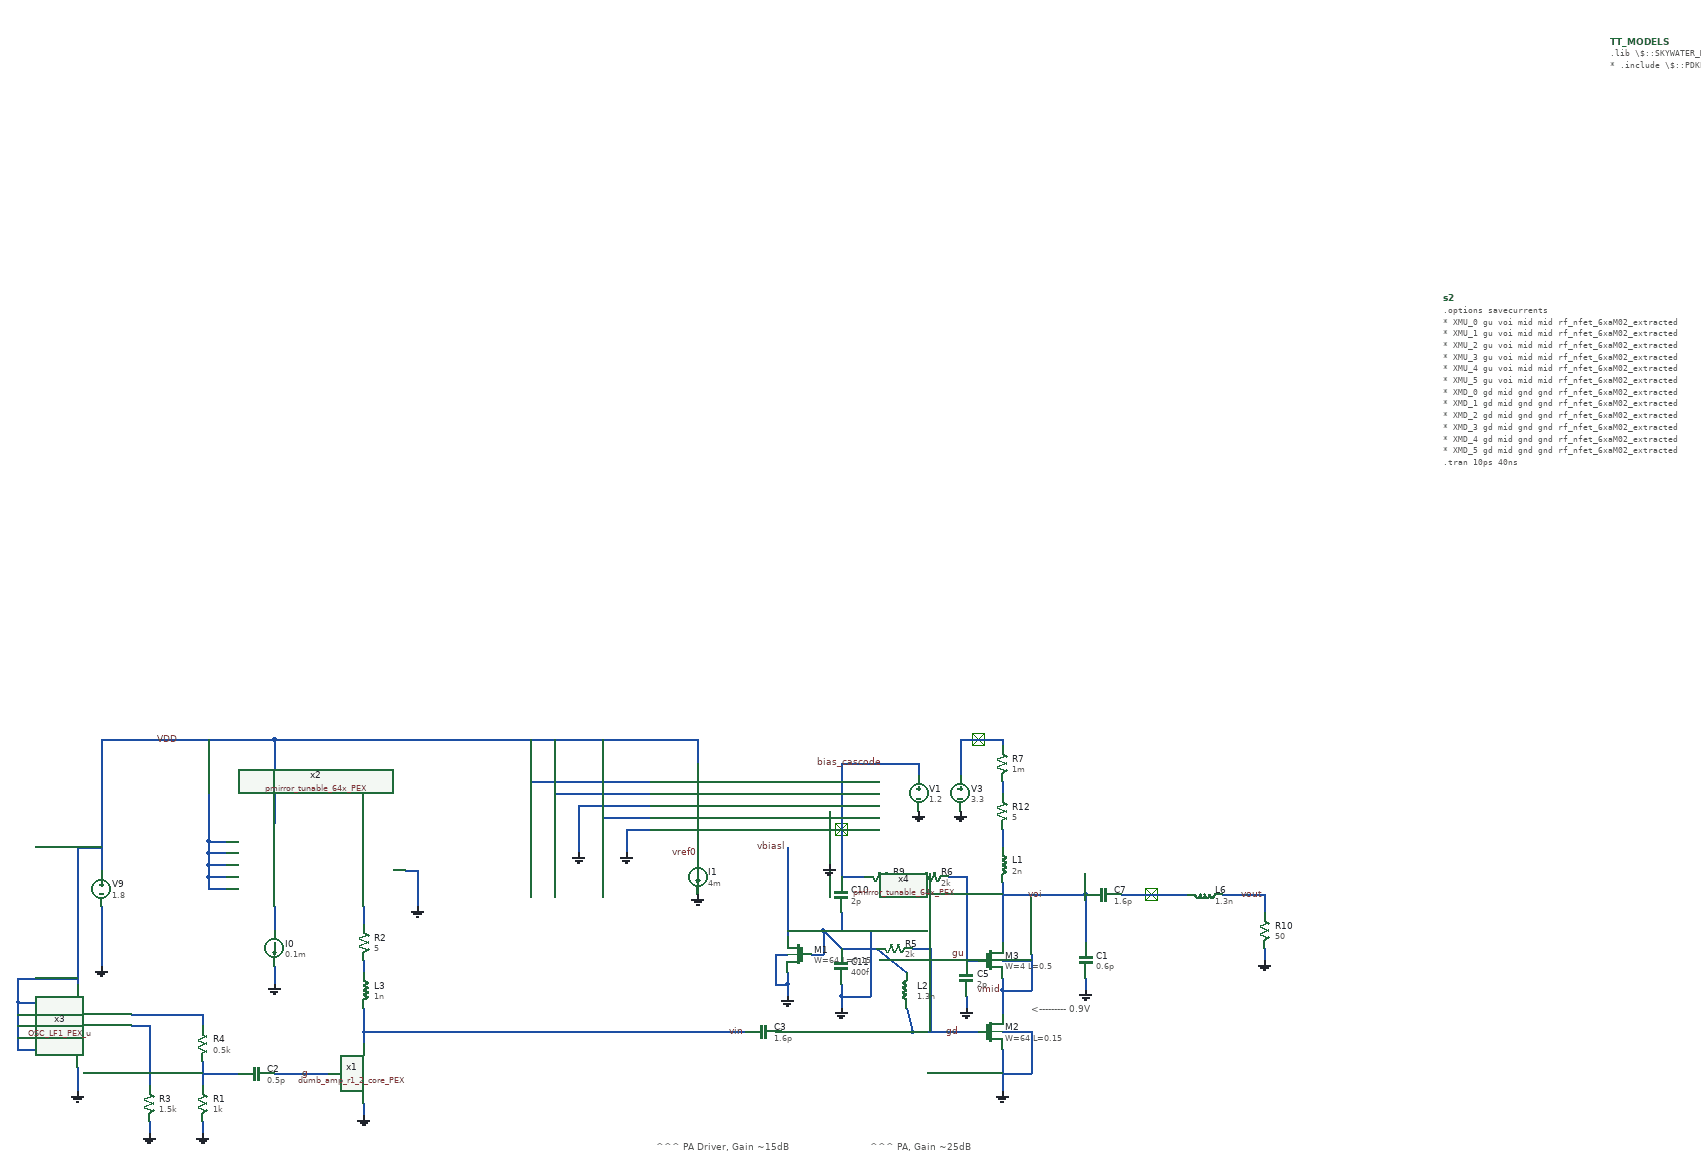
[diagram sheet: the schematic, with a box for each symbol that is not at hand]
v {xschem version=3.0.0 file_version=1.2 }
G {}
K {}
V {}
S {}
E {}
L 4 730 -310 730 -290 {}
L 4 730 -290 750 -290 {}
L 4 750 -310 750 -290 {}
L 4 730 -310 750 -310 {}
L 4 730 -310 750 -290 {}
L 4 750 -310 750 -290 {}
L 4 730 -290 750 -310 {}
L 4 1020 -50 1020 -30 {}
L 4 1020 -30 1040 -30 {}
L 4 1040 -50 1040 -30 {}
L 4 1020 -50 1040 -50 {}
L 4 1020 -50 1040 -30 {}
L 4 1020 -30 1040 -50 {}
L 4 500 -160 500 -140 {}
L 4 500 -140 520 -140 {}
L 4 520 -160 520 -140 {}
L 4 500 -160 520 -160 {}
L 4 500 -160 520 -140 {}
L 4 520 -160 520 -140 {}
L 4 500 -140 520 -160 {}
T {<--------- 0.9V} 830 140 0 0 0.4 0.4 {}
T {^^^ PA Driver, Gain ~15dB} 200 370 0 0 0.4 0.4 {}
T {^^^ PA, Gain ~25dB} 560 370 0 0 0.4 0.4 {}
N 780 -60 780 -10 {
lab=voi}
N 630 190 720 190 {
lab=gd}
N 710 -300 710 -240 {
lab=#net1}
N 710 -300 780 -300 {
lab=#net1}
N 1220 50 1220 70 {
lab=GND}
N 1150 -40 1220 -40 {
lab=vout}
N 1220 -40 1220 -10 {
lab=vout}
N 920 -40 920 -30 {
lab=voi}
N 830 60 830 120 {
lab=vmid}
N 780 120 830 120 {
lab=vmid}
N 920 100 920 120 {
lab=GND}
N 920 -40 920 40 {
lab=voi}
N 780 100 780 120 {
lab=vmid}
N 720 70 740 70 {
lab=gu}
N 720 60 720 70 {
lab=gu}
N 780 -10 780 40 {
lab=voi}
N 780 70 830 70 {
lab=vmid}
N 780 120 780 160 {
lab=vmid}
N 720 190 740 190 {
lab=gd}
N 780 220 780 250 {
lab=GND}
N 780 190 830 190 {
lab=GND}
N 720 130 720 150 {
lab=GND}
N 780 -300 780 -290 {
lab=#net1}
N 780 -230 780 -210 {
lab=#net2}
N 780 250 780 290 {
lab=GND}
N 780 -150 780 -120 {
lab=#net3}
N 420 -0 420 30 {
lab=vbiasl}
N 400 60 420 60 {
lab=GND}
N 400 60 400 110 {
lab=GND}
N 400 110 420 110 {
lab=GND}
N 420 90 420 110 {
lab=GND}
N 420 110 420 130 {
lab=GND}
N 460 60 480 60 {
lab=vbiasl}
N 480 20 480 60 {
lab=vbiasl}
N 420 20 480 20 {
lab=vbiasl}
N 510 -10 510 20 {
lab=GND}
N 510 20 560 20 {
lab=GND}
N 560 20 560 130 {
lab=GND}
N 510 130 560 130 {
lab=GND}
N 510 110 510 130 {
lab=GND}
N 510 130 510 150 {
lab=GND}
N 510 50 570 50 {
lab=vbiasl}
N 720 -70 720 60 {
lab=gu}
N 630 50 660 50 {
lab=gd}
N 660 50 660 190 {
lab=gd}
N 510 -70 550 -70 {
lab=bias_cascode}
N 830 190 830 260 {
lab=GND}
N 780 260 830 260 {
lab=GND}
N 400 190 480 190 {
lab=gd}
N 540 190 570 190 {
lab=gd}
N 480 190 510 190 {
lab=gd}
N 510 190 540 190 {
lab=gd}
N 480 20 510 50 {
lab=vbiasl}
N 270 190 280 190 {
lab=vin}
N 230 190 270 190 {
lab=vin}
N -440 -260 -440 -160 {
lab=VDD}
N 40 190 170 190 {
lab=vin}
N 280 190 350 190 {
lab=vin}
N 780 -40 920 -40 {
lab=voi}
N 620 150 630 190 {
lab=gd}
N 570 50 620 90 {
lab=vbiasl}
N 170 190 230 190 {
lab=vin}
N 980 -40 1090 -40 {
lab=#net4}
N -550 -260 -550 -130 {
lab=VDD}
N 690 -70 720 -70 {
lab=gu}
N 610 -70 630 -70 {
lab=#net5}
N 640 -260 640 -240 {
lab=bias_cascode}
N 590 -260 640 -260 {
lab=bias_cascode}
N 580 -260 590 -260 {
lab=bias_cascode}
N 510 -260 580 -260 {
lab=bias_cascode}
N 510 -260 510 -70 {
lab=bias_cascode}
N 490 -180 490 -90 {
lab=GND}
N 270 -300 270 -260 {
lab=VDD}
N -440 -300 270 -300 {
lab=VDD}
N -550 -300 -550 -260 {
lab=VDD}
N -440 -300 -440 -260 {
lab=VDD}
N 270 -120 270 -100 {
lab=vref0}
N -10 -230 190 -230 {
lab=G2}
N 30 -210 190 -210 {
lab=VDD}
N 70 -190 190 -190 {
lab=GND}
N 110 -170 190 -170 {
lab=VDD}
N 150 -150 190 -150 {
lab=GND}
N 420 -120 420 -0 {
lab=vbiasl}
N 150 -150 150 -110 {
lab=GND}
N 110 -300 110 -170 {
lab=VDD}
N 30 -300 30 -210 {
lab=VDD}
N -10 -300 -10 -230 {
lab=VDD}
N 70 -190 70 -110 {
lab=GND}
N -290 310 -290 330 {
lab=GND}
N -290 190 -250 190 {
lab=vin}
N -290 70 -290 90 {
lab=#net6}
N -440 80 -440 110 {
lab=GND}
N -440 -20 -440 20 {
lab=#net7}
N -730 -20 -730 80 {
lab=GND}
N -290 150 -290 190 {
lab=vin}
N -290 70 -290 90 {
lab=#net6}
N -440 80 -440 110 {
lab=GND}
N -290 150 -290 190 {
lab=vin}
N -560 240 -560 280 {
lab=#net8}
N -560 260 -500 260 {
lab=#net8}
N -560 340 -560 360 {
lab=GND}
N -680 160 -560 160 {
lab=#net9}
N -290 190 -290 210 {
lab=vin}
N -440 260 -350 260 {
lab=g}
N -290 -20 -290 10 {
lab=#net10}
N -220 -80 -200 -80 {
lab=GND}
N -200 -80 -200 -20 {
lab=GND}
N -550 -130 -520 -130 {
lab=VDD}
N -550 -130 -550 -110 {
lab=VDD}
N -550 -110 -520 -110 {
lab=VDD}
N -550 -110 -550 -90 {
lab=VDD}
N -550 -90 -520 -90 {
lab=VDD}
N -550 -90 -550 -70 {
lab=VDD}
N -550 -70 -520 -70 {
lab=VDD}
N -550 -70 -550 -50 {
lab=VDD}
N -550 -50 -520 -50 {
lab=VDD}
N -560 160 -560 180 {
lab=#net9}
N -650 340 -650 360 {
lab=GND}
N -650 180 -650 280 {
lab=#net11}
N -680 180 -650 180 {
lab=#net11}
N -770 -120 -770 110 {
lab=VDD}
N -770 -120 -730 -120 {
lab=VDD}
N -770 250 -770 290 {
lab=GND}
N -870 220 -840 220 {
lab=VDD}
N -870 140 -870 220 {
lab=VDD}
N -870 140 -840 140 {
lab=VDD}
N -870 160 -840 160 {
lab=VDD}
N -870 180 -840 180 {
lab=VDD}
N -870 200 -840 200 {
lab=VDD}
N -870 100 -870 140 {
lab=VDD}
N -870 100 -770 100 {
lab=VDD}
N -730 -300 -730 -80 {
lab=VDD}
N -730 -300 -440 -300 {
lab=VDD}
N -250 190 40 190 {
lab=vin}
N 570 190 630 190 {
lab=gd}
C {devices/code.sym} 1800 -1470 0 0 {name=TT_MODELS only_toplevel=false
format="tcleval(@value )" value=".lib \\\\$::SKYWATER_MODELS\\\\/sky130.lib.spice tt
* .include \\\\$::PDKPATH\\\\/libs.ref/sky130_fd_sc_hvl/spice/sky130_fd_sc_hvl.spice
"}
C {devices/code_shown.sym} 1520 -1040 0 0 {name=s2 only_toplevel=false value="
.options savecurrents
* XMU_0 gu voi mid mid rf_nfet_6xaM02_extracted
* XMU_1 gu voi mid mid rf_nfet_6xaM02_extracted
* XMU_2 gu voi mid mid rf_nfet_6xaM02_extracted
* XMU_3 gu voi mid mid rf_nfet_6xaM02_extracted
* XMU_4 gu voi mid mid rf_nfet_6xaM02_extracted
* XMU_5 gu voi mid mid rf_nfet_6xaM02_extracted
* XMD_0 gd mid gnd gnd rf_nfet_6xaM02_extracted
* XMD_1 gd mid gnd gnd rf_nfet_6xaM02_extracted
* XMD_2 gd mid gnd gnd rf_nfet_6xaM02_extracted
* XMD_3 gd mid gnd gnd rf_nfet_6xaM02_extracted
* XMD_4 gd mid gnd gnd rf_nfet_6xaM02_extracted
* XMD_5 gd mid gnd gnd rf_nfet_6xaM02_extracted
.tran 10ps 40ns
* .sp dec 1000 1e9 10e9 1
* .dc I1 0 10m 0.1m
.control
run
display
* plot @r5[i]
* let zout=@rload[r]
* let zin=50
* plot voi
* plot vout
* plot @c1[i]

plot vbiasl
plot @l1[i]


* meas TRAN vout_rms rms v(vout)
* meas TRAN isp_hi_avg  avg @r7[i]
* meas TRAN isp_mid_avg avg @r9[i]
* meas TRAN vin_rms rms v(vin)
* meas TRAN isp_1p8_avg avg @rsense2[i]
* let psp_rms  = isp_hi_avg*3.6 + isp_mid_avg*2.2 
* let pout_rms = vout_rms^2/zout
* let pin_rms  = vin_rms^2/zin
* print psp_rms
* print ((pout_rms-pin_rms)/psp_rms)*100
* print 10*log10(pout_rms*1000)

* plot gd vmid voi vout

* let pout = mag(@rload[i]*vout)
* let poutdbm = log10((pout/(1e-3))*10
* plot pout

.endc
"}
C {devices/gnd.sym} 780 290 0 0 {name=l1 lab=GND}
C {devices/vsource.sym} 710 -210 0 0 {name=V3 value=3.3}
C {devices/gnd.sym} 710 -180 0 0 {name=l5 lab=GND}
C {devices/gnd.sym} 1220 70 0 0 {name=l6 lab=GND}
C {devices/lab_wire.sym} 350 190 0 0 {name=l11 sig_type=std_logic lab=vin}
C {devices/ind.sym} 780 -90 0 0 {name=L1
m=1
value=2n
footprint=1206
device=inductor}
C {devices/ind.sym} 1120 -40 1 0 {name=L6
m=1
value=1.3n
footprint=1206
device=inductor}
C {devices/capa.sym} 950 -40 1 0 {name=C7
m=1
value=1.6p

footprint=1206
device="ceramic capacitor"}
C {devices/lab_wire.sym} 1220 -40 0 0 {name=l15 sig_type=std_logic lab=vout}
C {devices/capa.sym} 920 70 0 0 {name=C1
m=1
value=0.6p

footprint=1206
device="ceramic capacitor"}
C {devices/lab_wire.sym} 850 -40 0 0 {name=l12 sig_type=std_logic lab=voi}
C {devices/res.sym} 600 50 1 0 {name=R5
value=2k
footprint=1206
device=resistor
m=1}
C {devices/lab_wire.sym} 720 60 0 0 {name=l13 sig_type=std_logic lab=gu}
C {devices/lab_wire.sym} 780 120 0 0 {name=l19 sig_type=std_logic lab=vmid}
C {devices/lab_wire.sym} 710 190 0 0 {name=l20 sig_type=std_logic lab=gd}
C {sky130_fd_pr/nfet_03v3_nvt.sym} 760 70 0 0 {name=M3
L=0.5
W=4
nf=1
mult=128
ad="'int((nf+1)/2) * W/nf * 0.29'" 
pd="'2*int((nf+1)/2) * (W/nf + 0.29)'"
as="'int((nf+2)/2) * W/nf * 0.29'" 
ps="'2*int((nf+2)/2) * (W/nf + 0.29)'"
nrd="'0.29 / W'" nrs="'0.29 / W'"
sa=0 sb=0 sd=0
model=nfet_03v3_nvt
spiceprefix=X
}
C {devices/res.sym} 660 -70 1 0 {name=R6
value=2k
footprint=1206
device=resistor
m=1}
C {devices/capa.sym} 720 100 0 0 {name=C5
m=1
value=2p

footprint=1206
device="ceramic capacitor"}
C {devices/gnd.sym} 720 150 0 0 {name=l18 lab=GND}
C {devices/res.sym} 780 -260 0 0 {name=R7
value=1m
footprint=1206
device=resistor
m=1}
C {sky130_fd_pr/nfet_01v8.sym} 760 190 0 0 {name=M2
L=0.15
W=64
nf=1 
mult=8
ad="'int((nf+1)/2) * W/nf * 0.29'" 
pd="'2*int((nf+1)/2) * (W/nf + 0.29)'"
as="'int((nf+2)/2) * W/nf * 0.29'" 
ps="'2*int((nf+2)/2) * (W/nf + 0.29)'"
nrd="'0.29 / W'" nrs="'0.29 / W'"
sa=0 sb=0 sd=0
model=nfet_01v8
spiceprefix=X
}
C {devices/res.sym} 780 -180 0 0 {name=R12
value=5
footprint=1206
device=resistor
m=1}
C {sky130_fd_pr/nfet_01v8.sym} 440 60 0 1 {name=M1
L=0.15
W=64
nf=1 
mult=1
ad="'int((nf+1)/2) * W/nf * 0.29'" 
pd="'2*int((nf+1)/2) * (W/nf + 0.29)'"
as="'int((nf+2)/2) * W/nf * 0.29'" 
ps="'2*int((nf+2)/2) * (W/nf + 0.29)'"
nrd="'0.29 / W'" nrs="'0.29 / W'"
sa=0 sb=0 sd=0
model=nfet_01v8
spiceprefix=X
}
C {devices/gnd.sym} 420 130 0 0 {name=l23 lab=GND}
C {devices/capa.sym} 510 -40 0 0 {name=C10
m=1
value=2p

footprint=1206
device="ceramic capacitor"}
C {devices/capa.sym} 510 80 0 0 {name=C11
m=1
value=400f

footprint=1206
device="ceramic capacitor"}
C {devices/gnd.sym} 510 150 0 0 {name=l16 lab=GND}
C {devices/res.sym} 580 -70 1 0 {name=R9
value=1m
footprint=1206
device=resistor
m=1}
C {devices/lab_wire.sym} 580 -260 0 0 {name=l17 sig_type=std_logic lab=bias_cascode}
C {devices/lab_wire.sym} 420 -120 0 0 {name=l24 sig_type=std_logic lab=vbiasl}
C {devices/gnd.sym} 920 120 0 0 {name=l25 lab=GND}
C {devices/ind.sym} 620 120 2 0 {name=L2
m=1
value=1.3n
footprint=1206
device=inductor}
C {devices/res.sym} 1220 20 0 0 {name=R10
value=50
footprint=1206
device=resistor
m=1}
C {devices/lab_wire.sym} -600 -300 0 0 {name=l26 sig_type=std_logic lab=VDD}
C {devices/vsource.sym} 640 -210 0 0 {name=V1 value=1.2}
C {devices/gnd.sym} 640 -180 0 0 {name=l2 lab=GND}
C {pmirror_tunable_64x_PEX.sym} 340 -190 0 0 {name=x4}
C {devices/gnd.sym} 490 -90 0 0 {name=l3 lab=GND}
C {devices/isource.sym} 270 -70 0 0 {name=I1 value=4m}
C {devices/gnd.sym} 270 -40 0 0 {name=l4 lab=GND}
C {devices/lab_wire.sym} 270 -110 0 0 {name=l9 sig_type=std_logic lab=vref0}
C {devices/gnd.sym} 150 -110 0 0 {name=l32 lab=GND}
C {devices/gnd.sym} 70 -110 0 0 {name=l33 lab=GND}
C {devices/vsource.sym} -730 -50 0 0 {name=V9 value=1.8}
C {devices/gnd.sym} -290 330 0 0 {name=l34 lab=GND}
C {devices/gnd.sym} -730 80 0 0 {name=l35 lab=GND}
C {devices/ind.sym} -290 120 0 0 {name=L3
m=1
value=1n
footprint=1206
device=inductor}
C {devices/res.sym} -290 40 0 0 {name=R2
value=5
footprint=1206
device=resistor
m=1}
C {devices/lab_wire.sym} -380 260 0 0 {name=l36 sig_type=std_logic lab=g}
C {devices/isource.sym} -440 50 0 0 {name=I0 value=0.1m}
C {devices/gnd.sym} -440 110 0 0 {name=l38 lab=GND}
C {devices/res.sym} -560 210 0 0 {name=R4
value=0.5k
footprint=1206
device=resistor
m=1}
C {devices/gnd.sym} -440 110 0 0 {name=l39 lab=GND}
C {devices/res.sym} -560 310 0 0 {name=R1
value=1k
footprint=1206
device=resistor
m=1}
C {devices/gnd.sym} -560 360 0 0 {name=l40 lab=GND}
C {dumb_amp_r1_2_core_PEX.sym} -290 330 0 0 {name=x1}
C {pmirror_tunable_64x_PEX.sym} -370 -90 0 0 {name=x2}
C {devices/gnd.sym} -200 -20 0 0 {name=l41 lab=GND}
C {devices/capa.sym} -470 260 1 0 {name=C2
m=1
value=0.5p
footprint=1206
device="ceramic capacitor"}
C {OSC_LF1_PEX_u.sym} -690 180 0 0 {name=x3}
C {devices/res.sym} -650 310 0 0 {name=R3
value=1.5k
footprint=1206
device=resistor
m=1}
C {devices/gnd.sym} -650 360 0 0 {name=l42 lab=GND}
C {devices/gnd.sym} -770 290 0 0 {name=l43 lab=GND}
C {devices/capa.sym} 380 190 1 0 {name=C3
m=1
value=1.6p

footprint=1206
device="ceramic capacitor"}
